VERSION 5.7 ;
  NOWIREEXTENSIONATPIN ON ;
  DIVIDERCHAR "/" ;
  BUSBITCHARS "[]" ;
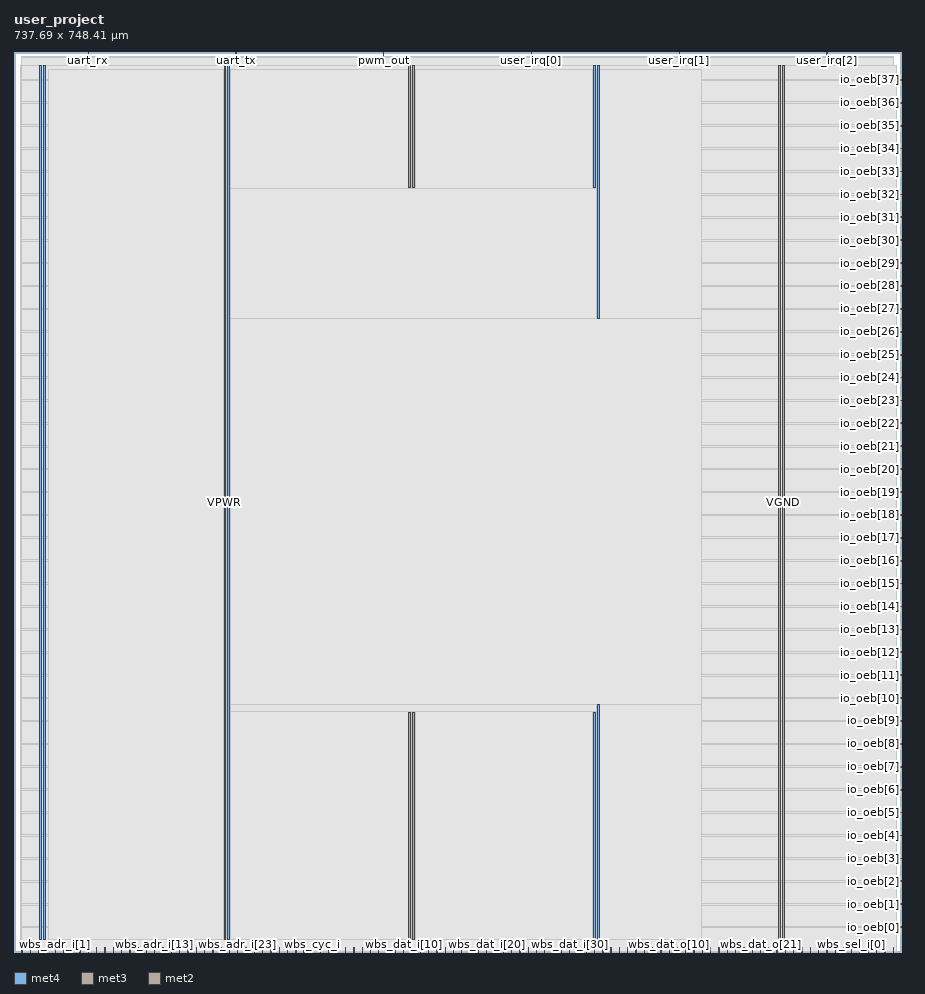
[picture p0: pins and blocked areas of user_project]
MACRO user_project
  CLASS BLOCK ;
  FOREIGN user_project ;
  ORIGIN 0.000 0.000 ;
  SIZE 737.690 BY 748.410 ;
  PIN VGND
    DIRECTION INOUT ;
    USE GROUND ;
    PORT
      LAYER met4 ;
        RECT 24.340 10.640 25.940 737.360 ;
    END
    PORT
      LAYER met4 ;
        RECT 177.940 10.640 179.540 737.360 ;
    END
    PORT
      LAYER met4 ;
        RECT 331.540 10.640 333.140 199.300 ;
    END
    PORT
      LAYER met4 ;
        RECT 331.540 635.700 333.140 737.360 ;
    END
    PORT
      LAYER met4 ;
        RECT 485.140 10.640 486.740 205.695 ;
    END
    PORT
      LAYER met4 ;
        RECT 485.140 526.825 486.740 737.360 ;
    END
    PORT
      LAYER met4 ;
        RECT 638.740 10.640 640.340 737.360 ;
    END
  END VGND
  PIN VPWR
    DIRECTION INOUT ;
    USE POWER ;
    PORT
      LAYER met4 ;
        RECT 21.040 10.640 22.640 737.360 ;
    END
    PORT
      LAYER met4 ;
        RECT 174.640 10.640 176.240 737.360 ;
    END
    PORT
      LAYER met4 ;
        RECT 328.240 10.640 329.840 199.300 ;
    END
    PORT
      LAYER met4 ;
        RECT 328.240 635.700 329.840 737.360 ;
    END
    PORT
      LAYER met4 ;
        RECT 481.840 10.640 483.440 199.300 ;
    END
    PORT
      LAYER met4 ;
        RECT 481.840 635.700 483.440 737.360 ;
    END
    PORT
      LAYER met4 ;
        RECT 635.440 10.640 637.040 737.360 ;
    END
  END VPWR
  PIN io_oeb[0]
    DIRECTION OUTPUT ;
    USE SIGNAL ;
    PORT
      LAYER met3 ;
        RECT 733.690 20.440 737.690 21.040 ;
    END
  END io_oeb[0]
  PIN io_oeb[10]
    DIRECTION OUTPUT ;
    USE SIGNAL ;
    PORT
      LAYER met3 ;
        RECT 733.690 210.840 737.690 211.440 ;
    END
  END io_oeb[10]
  PIN io_oeb[11]
    DIRECTION OUTPUT ;
    USE SIGNAL ;
    PORT
      LAYER met3 ;
        RECT 733.690 229.880 737.690 230.480 ;
    END
  END io_oeb[11]
  PIN io_oeb[12]
    DIRECTION OUTPUT ;
    USE SIGNAL ;
    PORT
      LAYER met3 ;
        RECT 733.690 248.920 737.690 249.520 ;
    END
  END io_oeb[12]
  PIN io_oeb[13]
    DIRECTION OUTPUT ;
    USE SIGNAL ;
    PORT
      LAYER met3 ;
        RECT 733.690 267.960 737.690 268.560 ;
    END
  END io_oeb[13]
  PIN io_oeb[14]
    DIRECTION OUTPUT ;
    USE SIGNAL ;
    PORT
      LAYER met3 ;
        RECT 733.690 287.000 737.690 287.600 ;
    END
  END io_oeb[14]
  PIN io_oeb[15]
    DIRECTION OUTPUT ;
    USE SIGNAL ;
    PORT
      LAYER met3 ;
        RECT 733.690 306.040 737.690 306.640 ;
    END
  END io_oeb[15]
  PIN io_oeb[16]
    DIRECTION OUTPUT ;
    USE SIGNAL ;
    PORT
      LAYER met3 ;
        RECT 733.690 325.080 737.690 325.680 ;
    END
  END io_oeb[16]
  PIN io_oeb[17]
    DIRECTION OUTPUT ;
    USE SIGNAL ;
    PORT
      LAYER met3 ;
        RECT 733.690 344.120 737.690 344.720 ;
    END
  END io_oeb[17]
  PIN io_oeb[18]
    DIRECTION OUTPUT ;
    USE SIGNAL ;
    PORT
      LAYER met3 ;
        RECT 733.690 363.160 737.690 363.760 ;
    END
  END io_oeb[18]
  PIN io_oeb[19]
    DIRECTION OUTPUT ;
    USE SIGNAL ;
    PORT
      LAYER met3 ;
        RECT 733.690 382.200 737.690 382.800 ;
    END
  END io_oeb[19]
  PIN io_oeb[1]
    DIRECTION OUTPUT ;
    USE SIGNAL ;
    PORT
      LAYER met3 ;
        RECT 733.690 39.480 737.690 40.080 ;
    END
  END io_oeb[1]
  PIN io_oeb[20]
    DIRECTION OUTPUT ;
    USE SIGNAL ;
    PORT
      LAYER met3 ;
        RECT 733.690 401.240 737.690 401.840 ;
    END
  END io_oeb[20]
  PIN io_oeb[21]
    DIRECTION OUTPUT ;
    USE SIGNAL ;
    PORT
      LAYER met3 ;
        RECT 733.690 420.280 737.690 420.880 ;
    END
  END io_oeb[21]
  PIN io_oeb[22]
    DIRECTION OUTPUT ;
    USE SIGNAL ;
    PORT
      LAYER met3 ;
        RECT 733.690 439.320 737.690 439.920 ;
    END
  END io_oeb[22]
  PIN io_oeb[23]
    DIRECTION OUTPUT ;
    USE SIGNAL ;
    PORT
      LAYER met3 ;
        RECT 733.690 458.360 737.690 458.960 ;
    END
  END io_oeb[23]
  PIN io_oeb[24]
    DIRECTION OUTPUT ;
    USE SIGNAL ;
    PORT
      LAYER met3 ;
        RECT 733.690 477.400 737.690 478.000 ;
    END
  END io_oeb[24]
  PIN io_oeb[25]
    DIRECTION OUTPUT ;
    USE SIGNAL ;
    PORT
      LAYER met3 ;
        RECT 733.690 496.440 737.690 497.040 ;
    END
  END io_oeb[25]
  PIN io_oeb[26]
    DIRECTION OUTPUT ;
    USE SIGNAL ;
    PORT
      LAYER met3 ;
        RECT 733.690 515.480 737.690 516.080 ;
    END
  END io_oeb[26]
  PIN io_oeb[27]
    DIRECTION OUTPUT ;
    USE SIGNAL ;
    PORT
      LAYER met3 ;
        RECT 733.690 534.520 737.690 535.120 ;
    END
  END io_oeb[27]
  PIN io_oeb[28]
    DIRECTION OUTPUT ;
    USE SIGNAL ;
    PORT
      LAYER met3 ;
        RECT 733.690 553.560 737.690 554.160 ;
    END
  END io_oeb[28]
  PIN io_oeb[29]
    DIRECTION OUTPUT ;
    USE SIGNAL ;
    PORT
      LAYER met3 ;
        RECT 733.690 572.600 737.690 573.200 ;
    END
  END io_oeb[29]
  PIN io_oeb[2]
    DIRECTION OUTPUT ;
    USE SIGNAL ;
    PORT
      LAYER met3 ;
        RECT 733.690 58.520 737.690 59.120 ;
    END
  END io_oeb[2]
  PIN io_oeb[30]
    DIRECTION OUTPUT ;
    USE SIGNAL ;
    PORT
      LAYER met3 ;
        RECT 733.690 591.640 737.690 592.240 ;
    END
  END io_oeb[30]
  PIN io_oeb[31]
    DIRECTION OUTPUT ;
    USE SIGNAL ;
    PORT
      LAYER met3 ;
        RECT 733.690 610.680 737.690 611.280 ;
    END
  END io_oeb[31]
  PIN io_oeb[32]
    DIRECTION OUTPUT ;
    USE SIGNAL ;
    PORT
      LAYER met3 ;
        RECT 733.690 629.720 737.690 630.320 ;
    END
  END io_oeb[32]
  PIN io_oeb[33]
    DIRECTION OUTPUT ;
    USE SIGNAL ;
    PORT
      LAYER met3 ;
        RECT 733.690 648.760 737.690 649.360 ;
    END
  END io_oeb[33]
  PIN io_oeb[34]
    DIRECTION OUTPUT ;
    USE SIGNAL ;
    PORT
      LAYER met3 ;
        RECT 733.690 667.800 737.690 668.400 ;
    END
  END io_oeb[34]
  PIN io_oeb[35]
    DIRECTION OUTPUT ;
    USE SIGNAL ;
    PORT
      LAYER met3 ;
        RECT 733.690 686.840 737.690 687.440 ;
    END
  END io_oeb[35]
  PIN io_oeb[36]
    DIRECTION OUTPUT ;
    USE SIGNAL ;
    PORT
      LAYER met3 ;
        RECT 733.690 705.880 737.690 706.480 ;
    END
  END io_oeb[36]
  PIN io_oeb[37]
    DIRECTION OUTPUT ;
    USE SIGNAL ;
    PORT
      LAYER met3 ;
        RECT 733.690 724.920 737.690 725.520 ;
    END
  END io_oeb[37]
  PIN io_oeb[3]
    DIRECTION OUTPUT ;
    USE SIGNAL ;
    PORT
      LAYER met3 ;
        RECT 733.690 77.560 737.690 78.160 ;
    END
  END io_oeb[3]
  PIN io_oeb[4]
    DIRECTION OUTPUT ;
    USE SIGNAL ;
    PORT
      LAYER met3 ;
        RECT 733.690 96.600 737.690 97.200 ;
    END
  END io_oeb[4]
  PIN io_oeb[5]
    DIRECTION OUTPUT ;
    USE SIGNAL ;
    PORT
      LAYER met3 ;
        RECT 733.690 115.640 737.690 116.240 ;
    END
  END io_oeb[5]
  PIN io_oeb[6]
    DIRECTION OUTPUT ;
    USE SIGNAL ;
    PORT
      LAYER met3 ;
        RECT 733.690 134.680 737.690 135.280 ;
    END
  END io_oeb[6]
  PIN io_oeb[7]
    DIRECTION OUTPUT ;
    USE SIGNAL ;
    PORT
      LAYER met3 ;
        RECT 733.690 153.720 737.690 154.320 ;
    END
  END io_oeb[7]
  PIN io_oeb[8]
    DIRECTION OUTPUT ;
    USE SIGNAL ;
    PORT
      LAYER met3 ;
        RECT 733.690 172.760 737.690 173.360 ;
    END
  END io_oeb[8]
  PIN io_oeb[9]
    DIRECTION OUTPUT ;
    USE SIGNAL ;
    PORT
      LAYER met3 ;
        RECT 733.690 191.800 737.690 192.400 ;
    END
  END io_oeb[9]
  PIN pwm_out
    DIRECTION OUTPUT ;
    USE SIGNAL ;
    ANTENNADIFFAREA 2.673000 ;
    PORT
      LAYER met2 ;
        RECT 307.370 744.410 307.650 748.410 ;
    END
  END pwm_out
  PIN uart_rx
    DIRECTION INPUT ;
    USE SIGNAL ;
    ANTENNAGATEAREA 0.647700 ;
    ANTENNADIFFAREA 0.434700 ;
    PORT
      LAYER met2 ;
        RECT 61.730 744.410 62.010 748.410 ;
    END
  END uart_rx
  PIN uart_tx
    DIRECTION OUTPUT ;
    USE SIGNAL ;
    ANTENNADIFFAREA 2.673000 ;
    PORT
      LAYER met2 ;
        RECT 184.550 744.410 184.830 748.410 ;
    END
  END uart_tx
  PIN user_irq[0]
    DIRECTION OUTPUT ;
    USE SIGNAL ;
    ANTENNADIFFAREA 2.673000 ;
    PORT
      LAYER met2 ;
        RECT 430.190 744.410 430.470 748.410 ;
    END
  END user_irq[0]
  PIN user_irq[1]
    DIRECTION OUTPUT ;
    USE SIGNAL ;
    ANTENNADIFFAREA 2.673000 ;
    PORT
      LAYER met2 ;
        RECT 553.010 744.410 553.290 748.410 ;
    END
  END user_irq[1]
  PIN user_irq[2]
    DIRECTION OUTPUT ;
    USE SIGNAL ;
    PORT
      LAYER met2 ;
        RECT 675.830 744.410 676.110 748.410 ;
    END
  END user_irq[2]
  PIN wb_clk_i
    DIRECTION INPUT ;
    USE SIGNAL ;
    ANTENNAGATEAREA 2.573400 ;
    ANTENNADIFFAREA 0.869400 ;
    PORT
      LAYER met2 ;
        RECT 6.530 0.000 6.810 4.000 ;
    END
  END wb_clk_i
  PIN wb_rst_i
    DIRECTION INPUT ;
    USE SIGNAL ;
    ANTENNAGATEAREA 0.682200 ;
    ANTENNADIFFAREA 0.434700 ;
    PORT
      LAYER met2 ;
        RECT 13.430 0.000 13.710 4.000 ;
    END
  END wb_rst_i
  PIN wbs_ack_o
    DIRECTION OUTPUT ;
    USE SIGNAL ;
    ANTENNADIFFAREA 2.673000 ;
    PORT
      LAYER met2 ;
        RECT 20.330 0.000 20.610 4.000 ;
    END
  END wbs_ack_o
  PIN wbs_adr_i[0]
    DIRECTION INPUT ;
    USE SIGNAL ;
    ANTENNAGATEAREA 0.560700 ;
    ANTENNADIFFAREA 0.434700 ;
    PORT
      LAYER met2 ;
        RECT 27.230 0.000 27.510 4.000 ;
    END
  END wbs_adr_i[0]
  PIN wbs_adr_i[10]
    DIRECTION INPUT ;
    USE SIGNAL ;
    ANTENNAGATEAREA 0.560700 ;
    ANTENNADIFFAREA 0.434700 ;
    PORT
      LAYER met2 ;
        RECT 96.230 0.000 96.510 4.000 ;
    END
  END wbs_adr_i[10]
  PIN wbs_adr_i[11]
    DIRECTION INPUT ;
    USE SIGNAL ;
    ANTENNAGATEAREA 0.560700 ;
    ANTENNADIFFAREA 0.434700 ;
    PORT
      LAYER met2 ;
        RECT 103.130 0.000 103.410 4.000 ;
    END
  END wbs_adr_i[11]
  PIN wbs_adr_i[12]
    DIRECTION INPUT ;
    USE SIGNAL ;
    ANTENNAGATEAREA 0.560700 ;
    ANTENNADIFFAREA 0.434700 ;
    PORT
      LAYER met2 ;
        RECT 110.030 0.000 110.310 4.000 ;
    END
  END wbs_adr_i[12]
  PIN wbs_adr_i[13]
    DIRECTION INPUT ;
    USE SIGNAL ;
    ANTENNAGATEAREA 0.647700 ;
    ANTENNADIFFAREA 0.434700 ;
    PORT
      LAYER met2 ;
        RECT 116.930 0.000 117.210 4.000 ;
    END
  END wbs_adr_i[13]
  PIN wbs_adr_i[14]
    DIRECTION INPUT ;
    USE SIGNAL ;
    ANTENNAGATEAREA 0.647700 ;
    ANTENNADIFFAREA 0.434700 ;
    PORT
      LAYER met2 ;
        RECT 123.830 0.000 124.110 4.000 ;
    END
  END wbs_adr_i[14]
  PIN wbs_adr_i[15]
    DIRECTION INPUT ;
    USE SIGNAL ;
    ANTENNAGATEAREA 0.560700 ;
    ANTENNADIFFAREA 0.434700 ;
    PORT
      LAYER met2 ;
        RECT 130.730 0.000 131.010 4.000 ;
    END
  END wbs_adr_i[15]
  PIN wbs_adr_i[16]
    DIRECTION INPUT ;
    USE SIGNAL ;
    ANTENNAGATEAREA 0.560700 ;
    ANTENNADIFFAREA 0.434700 ;
    PORT
      LAYER met2 ;
        RECT 137.630 0.000 137.910 4.000 ;
    END
  END wbs_adr_i[16]
  PIN wbs_adr_i[17]
    DIRECTION INPUT ;
    USE SIGNAL ;
    ANTENNAGATEAREA 0.560700 ;
    ANTENNADIFFAREA 0.434700 ;
    PORT
      LAYER met2 ;
        RECT 144.530 0.000 144.810 4.000 ;
    END
  END wbs_adr_i[17]
  PIN wbs_adr_i[18]
    DIRECTION INPUT ;
    USE SIGNAL ;
    ANTENNAGATEAREA 0.560700 ;
    ANTENNADIFFAREA 0.434700 ;
    PORT
      LAYER met2 ;
        RECT 151.430 0.000 151.710 4.000 ;
    END
  END wbs_adr_i[18]
  PIN wbs_adr_i[19]
    DIRECTION INPUT ;
    USE SIGNAL ;
    ANTENNAGATEAREA 0.560700 ;
    ANTENNADIFFAREA 0.434700 ;
    PORT
      LAYER met2 ;
        RECT 158.330 0.000 158.610 4.000 ;
    END
  END wbs_adr_i[19]
  PIN wbs_adr_i[1]
    DIRECTION INPUT ;
    USE SIGNAL ;
    ANTENNAGATEAREA 0.560700 ;
    ANTENNADIFFAREA 0.434700 ;
    PORT
      LAYER met2 ;
        RECT 34.130 0.000 34.410 4.000 ;
    END
  END wbs_adr_i[1]
  PIN wbs_adr_i[20]
    DIRECTION INPUT ;
    USE SIGNAL ;
    ANTENNAGATEAREA 0.647700 ;
    ANTENNADIFFAREA 0.434700 ;
    PORT
      LAYER met2 ;
        RECT 165.230 0.000 165.510 4.000 ;
    END
  END wbs_adr_i[20]
  PIN wbs_adr_i[21]
    DIRECTION INPUT ;
    USE SIGNAL ;
    ANTENNAGATEAREA 0.647700 ;
    ANTENNADIFFAREA 0.434700 ;
    PORT
      LAYER met2 ;
        RECT 172.130 0.000 172.410 4.000 ;
    END
  END wbs_adr_i[21]
  PIN wbs_adr_i[22]
    DIRECTION INPUT ;
    USE SIGNAL ;
    ANTENNAGATEAREA 0.647700 ;
    ANTENNADIFFAREA 0.434700 ;
    PORT
      LAYER met2 ;
        RECT 179.030 0.000 179.310 4.000 ;
    END
  END wbs_adr_i[22]
  PIN wbs_adr_i[23]
    DIRECTION INPUT ;
    USE SIGNAL ;
    ANTENNAGATEAREA 0.647700 ;
    ANTENNADIFFAREA 0.434700 ;
    PORT
      LAYER met2 ;
        RECT 185.930 0.000 186.210 4.000 ;
    END
  END wbs_adr_i[23]
  PIN wbs_adr_i[24]
    DIRECTION INPUT ;
    USE SIGNAL ;
    ANTENNAGATEAREA 0.647700 ;
    ANTENNADIFFAREA 0.434700 ;
    PORT
      LAYER met2 ;
        RECT 192.830 0.000 193.110 4.000 ;
    END
  END wbs_adr_i[24]
  PIN wbs_adr_i[25]
    DIRECTION INPUT ;
    USE SIGNAL ;
    ANTENNAGATEAREA 0.647700 ;
    ANTENNADIFFAREA 0.434700 ;
    PORT
      LAYER met2 ;
        RECT 199.730 0.000 200.010 4.000 ;
    END
  END wbs_adr_i[25]
  PIN wbs_adr_i[26]
    DIRECTION INPUT ;
    USE SIGNAL ;
    ANTENNAGATEAREA 0.647700 ;
    ANTENNADIFFAREA 0.434700 ;
    PORT
      LAYER met2 ;
        RECT 206.630 0.000 206.910 4.000 ;
    END
  END wbs_adr_i[26]
  PIN wbs_adr_i[27]
    DIRECTION INPUT ;
    USE SIGNAL ;
    ANTENNAGATEAREA 0.647700 ;
    ANTENNADIFFAREA 0.434700 ;
    PORT
      LAYER met2 ;
        RECT 213.530 0.000 213.810 4.000 ;
    END
  END wbs_adr_i[27]
  PIN wbs_adr_i[28]
    DIRECTION INPUT ;
    USE SIGNAL ;
    ANTENNAGATEAREA 0.647700 ;
    ANTENNADIFFAREA 0.434700 ;
    PORT
      LAYER met2 ;
        RECT 220.430 0.000 220.710 4.000 ;
    END
  END wbs_adr_i[28]
  PIN wbs_adr_i[29]
    DIRECTION INPUT ;
    USE SIGNAL ;
    ANTENNAGATEAREA 0.647700 ;
    ANTENNADIFFAREA 0.434700 ;
    PORT
      LAYER met2 ;
        RECT 227.330 0.000 227.610 4.000 ;
    END
  END wbs_adr_i[29]
  PIN wbs_adr_i[2]
    DIRECTION INPUT ;
    USE SIGNAL ;
    ANTENNAGATEAREA 0.560700 ;
    ANTENNADIFFAREA 0.434700 ;
    PORT
      LAYER met2 ;
        RECT 41.030 0.000 41.310 4.000 ;
    END
  END wbs_adr_i[2]
  PIN wbs_adr_i[30]
    DIRECTION INPUT ;
    USE SIGNAL ;
    ANTENNAGATEAREA 0.647700 ;
    ANTENNADIFFAREA 0.434700 ;
    PORT
      LAYER met2 ;
        RECT 234.230 0.000 234.510 4.000 ;
    END
  END wbs_adr_i[30]
  PIN wbs_adr_i[31]
    DIRECTION INPUT ;
    USE SIGNAL ;
    ANTENNAGATEAREA 0.647700 ;
    ANTENNADIFFAREA 0.434700 ;
    PORT
      LAYER met2 ;
        RECT 241.130 0.000 241.410 4.000 ;
    END
  END wbs_adr_i[31]
  PIN wbs_adr_i[3]
    DIRECTION INPUT ;
    USE SIGNAL ;
    ANTENNAGATEAREA 0.560700 ;
    ANTENNADIFFAREA 0.434700 ;
    PORT
      LAYER met2 ;
        RECT 47.930 0.000 48.210 4.000 ;
    END
  END wbs_adr_i[3]
  PIN wbs_adr_i[4]
    DIRECTION INPUT ;
    USE SIGNAL ;
    ANTENNAGATEAREA 0.560700 ;
    ANTENNADIFFAREA 0.434700 ;
    PORT
      LAYER met2 ;
        RECT 54.830 0.000 55.110 4.000 ;
    END
  END wbs_adr_i[4]
  PIN wbs_adr_i[5]
    DIRECTION INPUT ;
    USE SIGNAL ;
    ANTENNAGATEAREA 0.682200 ;
    ANTENNADIFFAREA 0.434700 ;
    PORT
      LAYER met2 ;
        RECT 61.730 0.000 62.010 4.000 ;
    END
  END wbs_adr_i[5]
  PIN wbs_adr_i[6]
    DIRECTION INPUT ;
    USE SIGNAL ;
    ANTENNAGATEAREA 0.560700 ;
    ANTENNADIFFAREA 0.434700 ;
    PORT
      LAYER met2 ;
        RECT 68.630 0.000 68.910 4.000 ;
    END
  END wbs_adr_i[6]
  PIN wbs_adr_i[7]
    DIRECTION INPUT ;
    USE SIGNAL ;
    ANTENNAGATEAREA 0.560700 ;
    ANTENNADIFFAREA 0.434700 ;
    PORT
      LAYER met2 ;
        RECT 75.530 0.000 75.810 4.000 ;
    END
  END wbs_adr_i[7]
  PIN wbs_adr_i[8]
    DIRECTION INPUT ;
    USE SIGNAL ;
    ANTENNAGATEAREA 0.560700 ;
    ANTENNADIFFAREA 0.434700 ;
    PORT
      LAYER met2 ;
        RECT 82.430 0.000 82.710 4.000 ;
    END
  END wbs_adr_i[8]
  PIN wbs_adr_i[9]
    DIRECTION INPUT ;
    USE SIGNAL ;
    ANTENNAGATEAREA 0.560700 ;
    ANTENNADIFFAREA 0.434700 ;
    PORT
      LAYER met2 ;
        RECT 89.330 0.000 89.610 4.000 ;
    END
  END wbs_adr_i[9]
  PIN wbs_cyc_i
    DIRECTION INPUT ;
    USE SIGNAL ;
    ANTENNAGATEAREA 0.560700 ;
    ANTENNADIFFAREA 0.434700 ;
    PORT
      LAYER met2 ;
        RECT 248.030 0.000 248.310 4.000 ;
    END
  END wbs_cyc_i
  PIN wbs_dat_i[0]
    DIRECTION INPUT ;
    USE SIGNAL ;
    ANTENNAGATEAREA 0.560700 ;
    ANTENNADIFFAREA 0.434700 ;
    PORT
      LAYER met2 ;
        RECT 254.930 0.000 255.210 4.000 ;
    END
  END wbs_dat_i[0]
  PIN wbs_dat_i[10]
    DIRECTION INPUT ;
    USE SIGNAL ;
    ANTENNAGATEAREA 0.560700 ;
    ANTENNADIFFAREA 0.434700 ;
    PORT
      LAYER met2 ;
        RECT 323.930 0.000 324.210 4.000 ;
    END
  END wbs_dat_i[10]
  PIN wbs_dat_i[11]
    DIRECTION INPUT ;
    USE SIGNAL ;
    ANTENNAGATEAREA 0.560700 ;
    ANTENNADIFFAREA 0.434700 ;
    PORT
      LAYER met2 ;
        RECT 330.830 0.000 331.110 4.000 ;
    END
  END wbs_dat_i[11]
  PIN wbs_dat_i[12]
    DIRECTION INPUT ;
    USE SIGNAL ;
    ANTENNAGATEAREA 0.560700 ;
    ANTENNADIFFAREA 0.434700 ;
    PORT
      LAYER met2 ;
        RECT 337.730 0.000 338.010 4.000 ;
    END
  END wbs_dat_i[12]
  PIN wbs_dat_i[13]
    DIRECTION INPUT ;
    USE SIGNAL ;
    ANTENNAGATEAREA 0.560700 ;
    ANTENNADIFFAREA 0.434700 ;
    PORT
      LAYER met2 ;
        RECT 344.630 0.000 344.910 4.000 ;
    END
  END wbs_dat_i[13]
  PIN wbs_dat_i[14]
    DIRECTION INPUT ;
    USE SIGNAL ;
    ANTENNAGATEAREA 0.560700 ;
    ANTENNADIFFAREA 0.434700 ;
    PORT
      LAYER met2 ;
        RECT 351.530 0.000 351.810 4.000 ;
    END
  END wbs_dat_i[14]
  PIN wbs_dat_i[15]
    DIRECTION INPUT ;
    USE SIGNAL ;
    ANTENNAGATEAREA 0.560700 ;
    ANTENNADIFFAREA 0.434700 ;
    PORT
      LAYER met2 ;
        RECT 358.430 0.000 358.710 4.000 ;
    END
  END wbs_dat_i[15]
  PIN wbs_dat_i[16]
    DIRECTION INPUT ;
    USE SIGNAL ;
    ANTENNAGATEAREA 0.560700 ;
    ANTENNADIFFAREA 0.434700 ;
    PORT
      LAYER met2 ;
        RECT 365.330 0.000 365.610 4.000 ;
    END
  END wbs_dat_i[16]
  PIN wbs_dat_i[17]
    DIRECTION INPUT ;
    USE SIGNAL ;
    ANTENNAGATEAREA 0.560700 ;
    ANTENNADIFFAREA 0.434700 ;
    PORT
      LAYER met2 ;
        RECT 372.230 0.000 372.510 4.000 ;
    END
  END wbs_dat_i[17]
  PIN wbs_dat_i[18]
    DIRECTION INPUT ;
    USE SIGNAL ;
    ANTENNAGATEAREA 0.560700 ;
    ANTENNADIFFAREA 0.434700 ;
    PORT
      LAYER met2 ;
        RECT 379.130 0.000 379.410 4.000 ;
    END
  END wbs_dat_i[18]
  PIN wbs_dat_i[19]
    DIRECTION INPUT ;
    USE SIGNAL ;
    ANTENNAGATEAREA 0.560700 ;
    ANTENNADIFFAREA 0.434700 ;
    PORT
      LAYER met2 ;
        RECT 386.030 0.000 386.310 4.000 ;
    END
  END wbs_dat_i[19]
  PIN wbs_dat_i[1]
    DIRECTION INPUT ;
    USE SIGNAL ;
    ANTENNAGATEAREA 0.560700 ;
    ANTENNADIFFAREA 0.434700 ;
    PORT
      LAYER met2 ;
        RECT 261.830 0.000 262.110 4.000 ;
    END
  END wbs_dat_i[1]
  PIN wbs_dat_i[20]
    DIRECTION INPUT ;
    USE SIGNAL ;
    ANTENNAGATEAREA 0.560700 ;
    ANTENNADIFFAREA 0.434700 ;
    PORT
      LAYER met2 ;
        RECT 392.930 0.000 393.210 4.000 ;
    END
  END wbs_dat_i[20]
  PIN wbs_dat_i[21]
    DIRECTION INPUT ;
    USE SIGNAL ;
    ANTENNAGATEAREA 0.560700 ;
    ANTENNADIFFAREA 0.434700 ;
    PORT
      LAYER met2 ;
        RECT 399.830 0.000 400.110 4.000 ;
    END
  END wbs_dat_i[21]
  PIN wbs_dat_i[22]
    DIRECTION INPUT ;
    USE SIGNAL ;
    ANTENNAGATEAREA 0.560700 ;
    ANTENNADIFFAREA 0.434700 ;
    PORT
      LAYER met2 ;
        RECT 406.730 0.000 407.010 4.000 ;
    END
  END wbs_dat_i[22]
  PIN wbs_dat_i[23]
    DIRECTION INPUT ;
    USE SIGNAL ;
    ANTENNAGATEAREA 0.560700 ;
    ANTENNADIFFAREA 0.434700 ;
    PORT
      LAYER met2 ;
        RECT 413.630 0.000 413.910 4.000 ;
    END
  END wbs_dat_i[23]
  PIN wbs_dat_i[24]
    DIRECTION INPUT ;
    USE SIGNAL ;
    ANTENNAGATEAREA 0.560700 ;
    ANTENNADIFFAREA 0.434700 ;
    PORT
      LAYER met2 ;
        RECT 420.530 0.000 420.810 4.000 ;
    END
  END wbs_dat_i[24]
  PIN wbs_dat_i[25]
    DIRECTION INPUT ;
    USE SIGNAL ;
    ANTENNAGATEAREA 0.560700 ;
    ANTENNADIFFAREA 0.434700 ;
    PORT
      LAYER met2 ;
        RECT 427.430 0.000 427.710 4.000 ;
    END
  END wbs_dat_i[25]
  PIN wbs_dat_i[26]
    DIRECTION INPUT ;
    USE SIGNAL ;
    ANTENNAGATEAREA 0.560700 ;
    ANTENNADIFFAREA 0.434700 ;
    PORT
      LAYER met2 ;
        RECT 434.330 0.000 434.610 4.000 ;
    END
  END wbs_dat_i[26]
  PIN wbs_dat_i[27]
    DIRECTION INPUT ;
    USE SIGNAL ;
    ANTENNAGATEAREA 0.560700 ;
    ANTENNADIFFAREA 0.434700 ;
    PORT
      LAYER met2 ;
        RECT 441.230 0.000 441.510 4.000 ;
    END
  END wbs_dat_i[27]
  PIN wbs_dat_i[28]
    DIRECTION INPUT ;
    USE SIGNAL ;
    ANTENNAGATEAREA 0.560700 ;
    ANTENNADIFFAREA 0.434700 ;
    PORT
      LAYER met2 ;
        RECT 448.130 0.000 448.410 4.000 ;
    END
  END wbs_dat_i[28]
  PIN wbs_dat_i[29]
    DIRECTION INPUT ;
    USE SIGNAL ;
    ANTENNAGATEAREA 0.560700 ;
    ANTENNADIFFAREA 0.434700 ;
    PORT
      LAYER met2 ;
        RECT 455.030 0.000 455.310 4.000 ;
    END
  END wbs_dat_i[29]
  PIN wbs_dat_i[2]
    DIRECTION INPUT ;
    USE SIGNAL ;
    ANTENNAGATEAREA 0.560700 ;
    ANTENNADIFFAREA 0.434700 ;
    PORT
      LAYER met2 ;
        RECT 268.730 0.000 269.010 4.000 ;
    END
  END wbs_dat_i[2]
  PIN wbs_dat_i[30]
    DIRECTION INPUT ;
    USE SIGNAL ;
    ANTENNAGATEAREA 0.560700 ;
    ANTENNADIFFAREA 0.434700 ;
    PORT
      LAYER met2 ;
        RECT 461.930 0.000 462.210 4.000 ;
    END
  END wbs_dat_i[30]
  PIN wbs_dat_i[31]
    DIRECTION INPUT ;
    USE SIGNAL ;
    ANTENNAGATEAREA 0.560700 ;
    ANTENNADIFFAREA 0.434700 ;
    PORT
      LAYER met2 ;
        RECT 468.830 0.000 469.110 4.000 ;
    END
  END wbs_dat_i[31]
  PIN wbs_dat_i[3]
    DIRECTION INPUT ;
    USE SIGNAL ;
    ANTENNAGATEAREA 0.560700 ;
    ANTENNADIFFAREA 0.434700 ;
    PORT
      LAYER met2 ;
        RECT 275.630 0.000 275.910 4.000 ;
    END
  END wbs_dat_i[3]
  PIN wbs_dat_i[4]
    DIRECTION INPUT ;
    USE SIGNAL ;
    ANTENNAGATEAREA 0.560700 ;
    ANTENNADIFFAREA 0.434700 ;
    PORT
      LAYER met2 ;
        RECT 282.530 0.000 282.810 4.000 ;
    END
  END wbs_dat_i[4]
  PIN wbs_dat_i[5]
    DIRECTION INPUT ;
    USE SIGNAL ;
    ANTENNAGATEAREA 0.560700 ;
    ANTENNADIFFAREA 0.434700 ;
    PORT
      LAYER met2 ;
        RECT 289.430 0.000 289.710 4.000 ;
    END
  END wbs_dat_i[5]
  PIN wbs_dat_i[6]
    DIRECTION INPUT ;
    USE SIGNAL ;
    ANTENNAGATEAREA 0.560700 ;
    ANTENNADIFFAREA 0.434700 ;
    PORT
      LAYER met2 ;
        RECT 296.330 0.000 296.610 4.000 ;
    END
  END wbs_dat_i[6]
  PIN wbs_dat_i[7]
    DIRECTION INPUT ;
    USE SIGNAL ;
    ANTENNAGATEAREA 0.560700 ;
    ANTENNADIFFAREA 0.434700 ;
    PORT
      LAYER met2 ;
        RECT 303.230 0.000 303.510 4.000 ;
    END
  END wbs_dat_i[7]
  PIN wbs_dat_i[8]
    DIRECTION INPUT ;
    USE SIGNAL ;
    ANTENNAGATEAREA 0.560700 ;
    ANTENNADIFFAREA 0.434700 ;
    PORT
      LAYER met2 ;
        RECT 310.130 0.000 310.410 4.000 ;
    END
  END wbs_dat_i[8]
  PIN wbs_dat_i[9]
    DIRECTION INPUT ;
    USE SIGNAL ;
    ANTENNAGATEAREA 0.560700 ;
    ANTENNADIFFAREA 0.434700 ;
    PORT
      LAYER met2 ;
        RECT 317.030 0.000 317.310 4.000 ;
    END
  END wbs_dat_i[9]
  PIN wbs_dat_o[0]
    DIRECTION OUTPUT ;
    USE SIGNAL ;
    ANTENNADIFFAREA 2.673000 ;
    PORT
      LAYER met2 ;
        RECT 475.730 0.000 476.010 4.000 ;
    END
  END wbs_dat_o[0]
  PIN wbs_dat_o[10]
    DIRECTION OUTPUT ;
    USE SIGNAL ;
    ANTENNADIFFAREA 2.673000 ;
    PORT
      LAYER met2 ;
        RECT 544.730 0.000 545.010 4.000 ;
    END
  END wbs_dat_o[10]
  PIN wbs_dat_o[11]
    DIRECTION OUTPUT ;
    USE SIGNAL ;
    ANTENNADIFFAREA 2.673000 ;
    PORT
      LAYER met2 ;
        RECT 551.630 0.000 551.910 4.000 ;
    END
  END wbs_dat_o[11]
  PIN wbs_dat_o[12]
    DIRECTION OUTPUT ;
    USE SIGNAL ;
    ANTENNADIFFAREA 2.673000 ;
    PORT
      LAYER met2 ;
        RECT 558.530 0.000 558.810 4.000 ;
    END
  END wbs_dat_o[12]
  PIN wbs_dat_o[13]
    DIRECTION OUTPUT ;
    USE SIGNAL ;
    ANTENNADIFFAREA 2.673000 ;
    PORT
      LAYER met2 ;
        RECT 565.430 0.000 565.710 4.000 ;
    END
  END wbs_dat_o[13]
  PIN wbs_dat_o[14]
    DIRECTION OUTPUT ;
    USE SIGNAL ;
    ANTENNADIFFAREA 2.673000 ;
    PORT
      LAYER met2 ;
        RECT 572.330 0.000 572.610 4.000 ;
    END
  END wbs_dat_o[14]
  PIN wbs_dat_o[15]
    DIRECTION OUTPUT ;
    USE SIGNAL ;
    ANTENNADIFFAREA 2.673000 ;
    PORT
      LAYER met2 ;
        RECT 579.230 0.000 579.510 4.000 ;
    END
  END wbs_dat_o[15]
  PIN wbs_dat_o[16]
    DIRECTION OUTPUT ;
    USE SIGNAL ;
    ANTENNADIFFAREA 2.673000 ;
    PORT
      LAYER met2 ;
        RECT 586.130 0.000 586.410 4.000 ;
    END
  END wbs_dat_o[16]
  PIN wbs_dat_o[17]
    DIRECTION OUTPUT ;
    USE SIGNAL ;
    ANTENNADIFFAREA 2.673000 ;
    PORT
      LAYER met2 ;
        RECT 593.030 0.000 593.310 4.000 ;
    END
  END wbs_dat_o[17]
  PIN wbs_dat_o[18]
    DIRECTION OUTPUT ;
    USE SIGNAL ;
    ANTENNADIFFAREA 2.673000 ;
    PORT
      LAYER met2 ;
        RECT 599.930 0.000 600.210 4.000 ;
    END
  END wbs_dat_o[18]
  PIN wbs_dat_o[19]
    DIRECTION OUTPUT ;
    USE SIGNAL ;
    ANTENNADIFFAREA 2.673000 ;
    PORT
      LAYER met2 ;
        RECT 606.830 0.000 607.110 4.000 ;
    END
  END wbs_dat_o[19]
  PIN wbs_dat_o[1]
    DIRECTION OUTPUT ;
    USE SIGNAL ;
    ANTENNADIFFAREA 2.673000 ;
    PORT
      LAYER met2 ;
        RECT 482.630 0.000 482.910 4.000 ;
    END
  END wbs_dat_o[1]
  PIN wbs_dat_o[20]
    DIRECTION OUTPUT ;
    USE SIGNAL ;
    ANTENNADIFFAREA 2.673000 ;
    PORT
      LAYER met2 ;
        RECT 613.730 0.000 614.010 4.000 ;
    END
  END wbs_dat_o[20]
  PIN wbs_dat_o[21]
    DIRECTION OUTPUT ;
    USE SIGNAL ;
    ANTENNADIFFAREA 2.673000 ;
    PORT
      LAYER met2 ;
        RECT 620.630 0.000 620.910 4.000 ;
    END
  END wbs_dat_o[21]
  PIN wbs_dat_o[22]
    DIRECTION OUTPUT ;
    USE SIGNAL ;
    ANTENNADIFFAREA 2.673000 ;
    PORT
      LAYER met2 ;
        RECT 627.530 0.000 627.810 4.000 ;
    END
  END wbs_dat_o[22]
  PIN wbs_dat_o[23]
    DIRECTION OUTPUT ;
    USE SIGNAL ;
    ANTENNADIFFAREA 2.673000 ;
    PORT
      LAYER met2 ;
        RECT 634.430 0.000 634.710 4.000 ;
    END
  END wbs_dat_o[23]
  PIN wbs_dat_o[24]
    DIRECTION OUTPUT ;
    USE SIGNAL ;
    ANTENNADIFFAREA 2.673000 ;
    PORT
      LAYER met2 ;
        RECT 641.330 0.000 641.610 4.000 ;
    END
  END wbs_dat_o[24]
  PIN wbs_dat_o[25]
    DIRECTION OUTPUT ;
    USE SIGNAL ;
    ANTENNADIFFAREA 2.673000 ;
    PORT
      LAYER met2 ;
        RECT 648.230 0.000 648.510 4.000 ;
    END
  END wbs_dat_o[25]
  PIN wbs_dat_o[26]
    DIRECTION OUTPUT ;
    USE SIGNAL ;
    ANTENNADIFFAREA 2.673000 ;
    PORT
      LAYER met2 ;
        RECT 655.130 0.000 655.410 4.000 ;
    END
  END wbs_dat_o[26]
  PIN wbs_dat_o[27]
    DIRECTION OUTPUT ;
    USE SIGNAL ;
    ANTENNADIFFAREA 2.673000 ;
    PORT
      LAYER met2 ;
        RECT 662.030 0.000 662.310 4.000 ;
    END
  END wbs_dat_o[27]
  PIN wbs_dat_o[28]
    DIRECTION OUTPUT ;
    USE SIGNAL ;
    ANTENNADIFFAREA 2.673000 ;
    PORT
      LAYER met2 ;
        RECT 668.930 0.000 669.210 4.000 ;
    END
  END wbs_dat_o[28]
  PIN wbs_dat_o[29]
    DIRECTION OUTPUT ;
    USE SIGNAL ;
    ANTENNADIFFAREA 2.673000 ;
    PORT
      LAYER met2 ;
        RECT 675.830 0.000 676.110 4.000 ;
    END
  END wbs_dat_o[29]
  PIN wbs_dat_o[2]
    DIRECTION OUTPUT ;
    USE SIGNAL ;
    ANTENNADIFFAREA 2.673000 ;
    PORT
      LAYER met2 ;
        RECT 489.530 0.000 489.810 4.000 ;
    END
  END wbs_dat_o[2]
  PIN wbs_dat_o[30]
    DIRECTION OUTPUT ;
    USE SIGNAL ;
    ANTENNADIFFAREA 2.673000 ;
    PORT
      LAYER met2 ;
        RECT 682.730 0.000 683.010 4.000 ;
    END
  END wbs_dat_o[30]
  PIN wbs_dat_o[31]
    DIRECTION OUTPUT ;
    USE SIGNAL ;
    ANTENNADIFFAREA 2.673000 ;
    PORT
      LAYER met2 ;
        RECT 689.630 0.000 689.910 4.000 ;
    END
  END wbs_dat_o[31]
  PIN wbs_dat_o[3]
    DIRECTION OUTPUT ;
    USE SIGNAL ;
    ANTENNADIFFAREA 2.673000 ;
    PORT
      LAYER met2 ;
        RECT 496.430 0.000 496.710 4.000 ;
    END
  END wbs_dat_o[3]
  PIN wbs_dat_o[4]
    DIRECTION OUTPUT ;
    USE SIGNAL ;
    ANTENNADIFFAREA 2.673000 ;
    PORT
      LAYER met2 ;
        RECT 503.330 0.000 503.610 4.000 ;
    END
  END wbs_dat_o[4]
  PIN wbs_dat_o[5]
    DIRECTION OUTPUT ;
    USE SIGNAL ;
    ANTENNADIFFAREA 2.673000 ;
    PORT
      LAYER met2 ;
        RECT 510.230 0.000 510.510 4.000 ;
    END
  END wbs_dat_o[5]
  PIN wbs_dat_o[6]
    DIRECTION OUTPUT ;
    USE SIGNAL ;
    ANTENNADIFFAREA 2.673000 ;
    PORT
      LAYER met2 ;
        RECT 517.130 0.000 517.410 4.000 ;
    END
  END wbs_dat_o[6]
  PIN wbs_dat_o[7]
    DIRECTION OUTPUT ;
    USE SIGNAL ;
    ANTENNADIFFAREA 2.673000 ;
    PORT
      LAYER met2 ;
        RECT 524.030 0.000 524.310 4.000 ;
    END
  END wbs_dat_o[7]
  PIN wbs_dat_o[8]
    DIRECTION OUTPUT ;
    USE SIGNAL ;
    ANTENNADIFFAREA 2.673000 ;
    PORT
      LAYER met2 ;
        RECT 530.930 0.000 531.210 4.000 ;
    END
  END wbs_dat_o[8]
  PIN wbs_dat_o[9]
    DIRECTION OUTPUT ;
    USE SIGNAL ;
    ANTENNADIFFAREA 2.673000 ;
    PORT
      LAYER met2 ;
        RECT 537.830 0.000 538.110 4.000 ;
    END
  END wbs_dat_o[9]
  PIN wbs_sel_i[0]
    DIRECTION INPUT ;
    USE SIGNAL ;
    ANTENNAGATEAREA 0.560700 ;
    ANTENNADIFFAREA 0.434700 ;
    PORT
      LAYER met2 ;
        RECT 696.530 0.000 696.810 4.000 ;
    END
  END wbs_sel_i[0]
  PIN wbs_sel_i[1]
    DIRECTION INPUT ;
    USE SIGNAL ;
    ANTENNAGATEAREA 0.560700 ;
    ANTENNADIFFAREA 0.434700 ;
    PORT
      LAYER met2 ;
        RECT 703.430 0.000 703.710 4.000 ;
    END
  END wbs_sel_i[1]
  PIN wbs_sel_i[2]
    DIRECTION INPUT ;
    USE SIGNAL ;
    ANTENNAGATEAREA 0.682200 ;
    ANTENNADIFFAREA 0.434700 ;
    PORT
      LAYER met2 ;
        RECT 710.330 0.000 710.610 4.000 ;
    END
  END wbs_sel_i[2]
  PIN wbs_sel_i[3]
    DIRECTION INPUT ;
    USE SIGNAL ;
    ANTENNAGATEAREA 0.682200 ;
    ANTENNADIFFAREA 0.434700 ;
    PORT
      LAYER met2 ;
        RECT 717.230 0.000 717.510 4.000 ;
    END
  END wbs_sel_i[3]
  PIN wbs_stb_i
    DIRECTION INPUT ;
    USE SIGNAL ;
    ANTENNAGATEAREA 0.860700 ;
    ANTENNADIFFAREA 0.434700 ;
    PORT
      LAYER met2 ;
        RECT 724.130 0.000 724.410 4.000 ;
    END
  END wbs_stb_i
  PIN wbs_we_i
    DIRECTION INPUT ;
    USE SIGNAL ;
    ANTENNAGATEAREA 0.560700 ;
    ANTENNADIFFAREA 0.434700 ;
    PORT
      LAYER met2 ;
        RECT 731.030 0.000 731.310 4.000 ;
    END
  END wbs_we_i
  OBS
      LAYER nwell ;
        RECT 5.330 10.795 732.050 737.310 ;
      LAYER li1 ;
        RECT 5.520 10.795 731.860 737.205 ;
      LAYER met1 ;
        RECT 5.520 8.200 731.860 737.360 ;
      LAYER met2 ;
        RECT 6.070 744.130 61.450 745.010 ;
        RECT 62.290 744.130 184.270 745.010 ;
        RECT 185.110 744.130 307.090 745.010 ;
        RECT 307.930 744.130 429.910 745.010 ;
        RECT 430.750 744.130 552.730 745.010 ;
        RECT 553.570 744.130 675.550 745.010 ;
        RECT 676.390 744.130 731.300 745.010 ;
        RECT 6.070 4.280 731.300 744.130 ;
        RECT 6.070 0.155 6.250 4.280 ;
        RECT 7.090 0.155 13.150 4.280 ;
        RECT 13.990 0.155 20.050 4.280 ;
        RECT 20.890 0.155 26.950 4.280 ;
        RECT 27.790 0.155 33.850 4.280 ;
        RECT 34.690 0.155 40.750 4.280 ;
        RECT 41.590 0.155 47.650 4.280 ;
        RECT 48.490 0.155 54.550 4.280 ;
        RECT 55.390 0.155 61.450 4.280 ;
        RECT 62.290 0.155 68.350 4.280 ;
        RECT 69.190 0.155 75.250 4.280 ;
        RECT 76.090 0.155 82.150 4.280 ;
        RECT 82.990 0.155 89.050 4.280 ;
        RECT 89.890 0.155 95.950 4.280 ;
        RECT 96.790 0.155 102.850 4.280 ;
        RECT 103.690 0.155 109.750 4.280 ;
        RECT 110.590 0.155 116.650 4.280 ;
        RECT 117.490 0.155 123.550 4.280 ;
        RECT 124.390 0.155 130.450 4.280 ;
        RECT 131.290 0.155 137.350 4.280 ;
        RECT 138.190 0.155 144.250 4.280 ;
        RECT 145.090 0.155 151.150 4.280 ;
        RECT 151.990 0.155 158.050 4.280 ;
        RECT 158.890 0.155 164.950 4.280 ;
        RECT 165.790 0.155 171.850 4.280 ;
        RECT 172.690 0.155 178.750 4.280 ;
        RECT 179.590 0.155 185.650 4.280 ;
        RECT 186.490 0.155 192.550 4.280 ;
        RECT 193.390 0.155 199.450 4.280 ;
        RECT 200.290 0.155 206.350 4.280 ;
        RECT 207.190 0.155 213.250 4.280 ;
        RECT 214.090 0.155 220.150 4.280 ;
        RECT 220.990 0.155 227.050 4.280 ;
        RECT 227.890 0.155 233.950 4.280 ;
        RECT 234.790 0.155 240.850 4.280 ;
        RECT 241.690 0.155 247.750 4.280 ;
        RECT 248.590 0.155 254.650 4.280 ;
        RECT 255.490 0.155 261.550 4.280 ;
        RECT 262.390 0.155 268.450 4.280 ;
        RECT 269.290 0.155 275.350 4.280 ;
        RECT 276.190 0.155 282.250 4.280 ;
        RECT 283.090 0.155 289.150 4.280 ;
        RECT 289.990 0.155 296.050 4.280 ;
        RECT 296.890 0.155 302.950 4.280 ;
        RECT 303.790 0.155 309.850 4.280 ;
        RECT 310.690 0.155 316.750 4.280 ;
        RECT 317.590 0.155 323.650 4.280 ;
        RECT 324.490 0.155 330.550 4.280 ;
        RECT 331.390 0.155 337.450 4.280 ;
        RECT 338.290 0.155 344.350 4.280 ;
        RECT 345.190 0.155 351.250 4.280 ;
        RECT 352.090 0.155 358.150 4.280 ;
        RECT 358.990 0.155 365.050 4.280 ;
        RECT 365.890 0.155 371.950 4.280 ;
        RECT 372.790 0.155 378.850 4.280 ;
        RECT 379.690 0.155 385.750 4.280 ;
        RECT 386.590 0.155 392.650 4.280 ;
        RECT 393.490 0.155 399.550 4.280 ;
        RECT 400.390 0.155 406.450 4.280 ;
        RECT 407.290 0.155 413.350 4.280 ;
        RECT 414.190 0.155 420.250 4.280 ;
        RECT 421.090 0.155 427.150 4.280 ;
        RECT 427.990 0.155 434.050 4.280 ;
        RECT 434.890 0.155 440.950 4.280 ;
        RECT 441.790 0.155 447.850 4.280 ;
        RECT 448.690 0.155 454.750 4.280 ;
        RECT 455.590 0.155 461.650 4.280 ;
        RECT 462.490 0.155 468.550 4.280 ;
        RECT 469.390 0.155 475.450 4.280 ;
        RECT 476.290 0.155 482.350 4.280 ;
        RECT 483.190 0.155 489.250 4.280 ;
        RECT 490.090 0.155 496.150 4.280 ;
        RECT 496.990 0.155 503.050 4.280 ;
        RECT 503.890 0.155 509.950 4.280 ;
        RECT 510.790 0.155 516.850 4.280 ;
        RECT 517.690 0.155 523.750 4.280 ;
        RECT 524.590 0.155 530.650 4.280 ;
        RECT 531.490 0.155 537.550 4.280 ;
        RECT 538.390 0.155 544.450 4.280 ;
        RECT 545.290 0.155 551.350 4.280 ;
        RECT 552.190 0.155 558.250 4.280 ;
        RECT 559.090 0.155 565.150 4.280 ;
        RECT 565.990 0.155 572.050 4.280 ;
        RECT 572.890 0.155 578.950 4.280 ;
        RECT 579.790 0.155 585.850 4.280 ;
        RECT 586.690 0.155 592.750 4.280 ;
        RECT 593.590 0.155 599.650 4.280 ;
        RECT 600.490 0.155 606.550 4.280 ;
        RECT 607.390 0.155 613.450 4.280 ;
        RECT 614.290 0.155 620.350 4.280 ;
        RECT 621.190 0.155 627.250 4.280 ;
        RECT 628.090 0.155 634.150 4.280 ;
        RECT 634.990 0.155 641.050 4.280 ;
        RECT 641.890 0.155 647.950 4.280 ;
        RECT 648.790 0.155 654.850 4.280 ;
        RECT 655.690 0.155 661.750 4.280 ;
        RECT 662.590 0.155 668.650 4.280 ;
        RECT 669.490 0.155 675.550 4.280 ;
        RECT 676.390 0.155 682.450 4.280 ;
        RECT 683.290 0.155 689.350 4.280 ;
        RECT 690.190 0.155 696.250 4.280 ;
        RECT 697.090 0.155 703.150 4.280 ;
        RECT 703.990 0.155 710.050 4.280 ;
        RECT 710.890 0.155 716.950 4.280 ;
        RECT 717.790 0.155 723.850 4.280 ;
        RECT 724.690 0.155 730.750 4.280 ;
      LAYER met3 ;
        RECT 6.045 725.920 733.690 737.285 ;
        RECT 6.045 724.520 733.290 725.920 ;
        RECT 6.045 706.880 733.690 724.520 ;
        RECT 6.045 705.480 733.290 706.880 ;
        RECT 6.045 687.840 733.690 705.480 ;
        RECT 6.045 686.440 733.290 687.840 ;
        RECT 6.045 668.800 733.690 686.440 ;
        RECT 6.045 667.400 733.290 668.800 ;
        RECT 6.045 649.760 733.690 667.400 ;
        RECT 6.045 648.360 733.290 649.760 ;
        RECT 6.045 630.720 733.690 648.360 ;
        RECT 6.045 629.320 733.290 630.720 ;
        RECT 6.045 611.680 733.690 629.320 ;
        RECT 6.045 610.280 733.290 611.680 ;
        RECT 6.045 592.640 733.690 610.280 ;
        RECT 6.045 591.240 733.290 592.640 ;
        RECT 6.045 573.600 733.690 591.240 ;
        RECT 6.045 572.200 733.290 573.600 ;
        RECT 6.045 554.560 733.690 572.200 ;
        RECT 6.045 553.160 733.290 554.560 ;
        RECT 6.045 535.520 733.690 553.160 ;
        RECT 6.045 534.120 733.290 535.520 ;
        RECT 6.045 516.480 733.690 534.120 ;
        RECT 6.045 515.080 733.290 516.480 ;
        RECT 6.045 497.440 733.690 515.080 ;
        RECT 6.045 496.040 733.290 497.440 ;
        RECT 6.045 478.400 733.690 496.040 ;
        RECT 6.045 477.000 733.290 478.400 ;
        RECT 6.045 459.360 733.690 477.000 ;
        RECT 6.045 457.960 733.290 459.360 ;
        RECT 6.045 440.320 733.690 457.960 ;
        RECT 6.045 438.920 733.290 440.320 ;
        RECT 6.045 421.280 733.690 438.920 ;
        RECT 6.045 419.880 733.290 421.280 ;
        RECT 6.045 402.240 733.690 419.880 ;
        RECT 6.045 400.840 733.290 402.240 ;
        RECT 6.045 383.200 733.690 400.840 ;
        RECT 6.045 381.800 733.290 383.200 ;
        RECT 6.045 364.160 733.690 381.800 ;
        RECT 6.045 362.760 733.290 364.160 ;
        RECT 6.045 345.120 733.690 362.760 ;
        RECT 6.045 343.720 733.290 345.120 ;
        RECT 6.045 326.080 733.690 343.720 ;
        RECT 6.045 324.680 733.290 326.080 ;
        RECT 6.045 307.040 733.690 324.680 ;
        RECT 6.045 305.640 733.290 307.040 ;
        RECT 6.045 288.000 733.690 305.640 ;
        RECT 6.045 286.600 733.290 288.000 ;
        RECT 6.045 268.960 733.690 286.600 ;
        RECT 6.045 267.560 733.290 268.960 ;
        RECT 6.045 249.920 733.690 267.560 ;
        RECT 6.045 248.520 733.290 249.920 ;
        RECT 6.045 230.880 733.690 248.520 ;
        RECT 6.045 229.480 733.290 230.880 ;
        RECT 6.045 211.840 733.690 229.480 ;
        RECT 6.045 210.440 733.290 211.840 ;
        RECT 6.045 192.800 733.690 210.440 ;
        RECT 6.045 191.400 733.290 192.800 ;
        RECT 6.045 173.760 733.690 191.400 ;
        RECT 6.045 172.360 733.290 173.760 ;
        RECT 6.045 154.720 733.690 172.360 ;
        RECT 6.045 153.320 733.290 154.720 ;
        RECT 6.045 135.680 733.690 153.320 ;
        RECT 6.045 134.280 733.290 135.680 ;
        RECT 6.045 116.640 733.690 134.280 ;
        RECT 6.045 115.240 733.290 116.640 ;
        RECT 6.045 97.600 733.690 115.240 ;
        RECT 6.045 96.200 733.290 97.600 ;
        RECT 6.045 78.560 733.690 96.200 ;
        RECT 6.045 77.160 733.290 78.560 ;
        RECT 6.045 59.520 733.690 77.160 ;
        RECT 6.045 58.120 733.290 59.520 ;
        RECT 6.045 40.480 733.690 58.120 ;
        RECT 6.045 39.080 733.290 40.480 ;
        RECT 6.045 21.440 733.690 39.080 ;
        RECT 6.045 20.040 733.290 21.440 ;
        RECT 6.045 0.175 733.690 20.040 ;
      LAYER met4 ;
        RECT 28.815 10.240 174.240 733.545 ;
        RECT 176.640 10.240 177.540 733.545 ;
        RECT 179.940 635.300 327.840 733.545 ;
        RECT 330.240 635.300 331.140 733.545 ;
        RECT 333.540 635.300 481.440 733.545 ;
        RECT 483.840 635.300 484.740 733.545 ;
        RECT 179.940 526.425 484.740 635.300 ;
        RECT 487.140 526.425 571.610 733.545 ;
        RECT 179.940 206.095 571.610 526.425 ;
        RECT 179.940 199.700 484.740 206.095 ;
        RECT 179.940 10.240 327.840 199.700 ;
        RECT 330.240 10.240 331.140 199.700 ;
        RECT 333.540 10.240 481.440 199.700 ;
        RECT 483.840 10.240 484.740 199.700 ;
        RECT 487.140 10.240 571.610 206.095 ;
        RECT 28.815 0.175 571.610 10.240 ;
  END
END user_project
END LIBRARY

